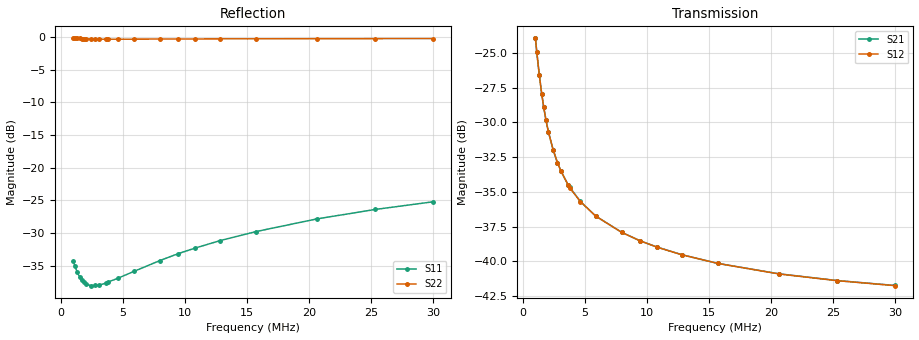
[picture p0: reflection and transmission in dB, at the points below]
! ListType=Log
!!FT114-43 11T Balun
# MHZ S RI R 50
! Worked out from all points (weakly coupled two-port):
!   101 points, 1 MHz to 30 MHz, reference 50 ohm
!   highest |S21| = -23.95 dB at 1 MHz (marker M1); lowest = -41.7 dB at 30 MHz (marker M2)
!   lowest |S11| = -38.1 dB at 2.421 MHz (marker M3), VSWR 1.03, Z = 49.8 + j1.23 ohm
!   |S11| at or under -10 dB: start of sweep to end of sweep
!   |S22| runs from -0.3 to -0.2 dB; largest |S21 - S12| = 2.1e-05
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1  -0.00408 0.0188  0.0143 -0.0618  0.0143 -0.0618  0.9448 0.2461
1.107423  -0.00344 0.0174  0.0123 -0.0554  0.0123 -0.0554  0.9526 0.22
1.312713  -0.00272 0.0156  0.0103 -0.0457  0.0103 -0.0457  0.9608 0.1807
1.504023  -0.00235 0.0143  0.00953 -0.039  0.00952 -0.039  0.9638 0.1534
1.66559  -0.00215 0.0136  0.00935 -0.0347  0.00934 -0.0347  0.9645 0.1356
1.844513  -0.00205 0.0131  0.00938 -0.0309  0.00936 -0.0309  0.9643 0.1202
2.042657  -0.00185 0.0127  0.00949 -0.0277  0.00947 -0.0277  0.9639 0.1068
2.421316  -0.00161 0.0124  0.0097 -0.0233  0.00969 -0.0233  0.963 0.0883
2.774191  -0.00132 0.0125  0.00982 -0.0204  0.00981 -0.0204  0.9625 0.076
3.072204  -0.00106 0.0126  0.00987 -0.0186  0.00985 -0.0186  0.9623 0.068
3.641716  -0.000585 0.0131  0.00988 -0.016  0.00987 -0.016  0.9622 0.0564
3.767708  -0.000462 0.0133  0.00988 -0.0156  0.00986 -0.0155  0.9623 0.0543
4.620666  0.000335 0.0143  0.00976 -0.0132  0.00974 -0.0132  0.9627 0.0429
5.862773  0.00153 0.016  0.0095 -0.011  0.00949 -0.011  0.9638 0.0316
7.9624  0.00373 0.0191  0.00903 -0.00893  0.00902 -0.00893  0.9657 0.0187
9.438436  0.00547 0.0213  0.00872 -0.00802  0.00871 -0.00802  0.9669 0.0119
10.81396  0.00716 0.0232  0.00847 -0.00739  0.00846 -0.00739  0.9679 0.00637
12.81861  0.00979 0.0259  0.00815 -0.0067  0.00814 -0.0067  0.9691 -0.000872
15.72057  0.014 0.0293  0.00777 -0.006  0.00777 -0.006  0.9704 -0.01
20.63659  0.0222 0.034  0.00731 -0.00527  0.0073 -0.00526  0.9719 -0.0238
25.30843  0.0308 0.0367  0.007 -0.00486  0.00699 -0.00486  0.9726 -0.0358
30  0.0401 0.0375  0.00675 -0.00462  0.00674 -0.00461  0.9731 -0.0471
